One B-rep face of a CAD part: STEP entity #914.
In plain terms, the planar face has unit normal (1, 0, 0).
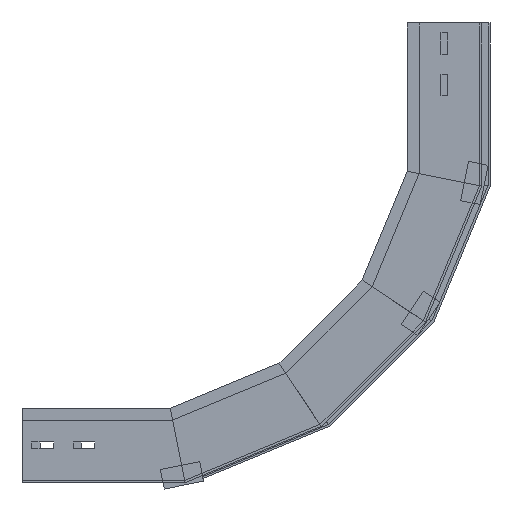
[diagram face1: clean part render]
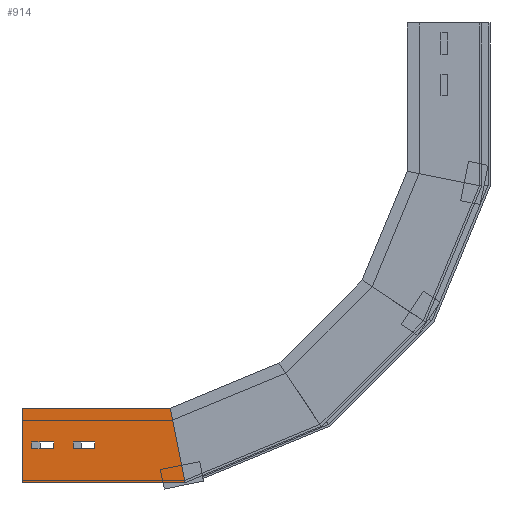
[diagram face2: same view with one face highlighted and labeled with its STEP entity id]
Its self-contained STEP definition (entity closure, numbers rounded to 3 decimals):
#3 = EDGE_CURVE ( 'NONE', #1530, #522, #280, .T. ) ;
#11 = CARTESIAN_POINT ( 'NONE',  ( 0., 41., -31.835 ) ) ;
#18 = ORIENTED_EDGE ( 'NONE', *, *, #1451, .T. ) ;
#43 = PLANE ( 'NONE',  #608 ) ;
#54 = CARTESIAN_POINT ( 'NONE',  ( 0., 0., -164.6 ) ) ;
#83 = CARTESIAN_POINT ( 'NONE',  ( 0., 41., -73.505 ) ) ;
#112 = CARTESIAN_POINT ( 'NONE',  ( 0., 34., -73.505 ) ) ;
#125 = DIRECTION ( 'NONE',  ( 0., -1., 0. ) ) ;
#147 = VERTEX_POINT ( 'NONE', #1470 ) ;
#148 = VECTOR ( 'NONE', #1207, 1000. ) ;
#162 = DIRECTION ( 'NONE',  ( -1., 0., 0. ) ) ;
#205 = FACE_BOUND ( 'NONE', #777, .T. ) ;
#280 = LINE ( 'NONE', #1710, #698 ) ;
#296 = CARTESIAN_POINT ( 'NONE',  ( 0., 75., 0. ) ) ;
#346 = ORIENTED_EDGE ( 'NONE', *, *, #1450, .F. ) ;
#369 = EDGE_CURVE ( 'NONE', #1091, #568, #1124, .T. ) ;
#379 = EDGE_CURVE ( 'NONE', #852, #602, #1860, .T. ) ;
#391 = VECTOR ( 'NONE', #1684, 1000. ) ;
#394 = CARTESIAN_POINT ( 'NONE',  ( 0., 0., 0. ) ) ;
#437 = EDGE_LOOP ( 'NONE', ( #1724, #1881, #18, #621 ) ) ;
#443 = LINE ( 'NONE', #1337, #1491 ) ;
#459 = CARTESIAN_POINT ( 'NONE',  ( 0., 0., 0. ) ) ;
#468 = DIRECTION ( 'NONE',  ( 0., 0., 1. ) ) ;
#469 = VERTEX_POINT ( 'NONE', #737 ) ;
#482 = LINE ( 'NONE', #781, #148 ) ;
#497 = CARTESIAN_POINT ( 'NONE',  ( 0., 75., -149.682 ) ) ;
#520 = CARTESIAN_POINT ( 'NONE',  ( 0., 41., -31.835 ) ) ;
#522 = VERTEX_POINT ( 'NONE', #1769 ) ;
#568 = VERTEX_POINT ( 'NONE', #54 ) ;
#575 = VECTOR ( 'NONE', #1275, 1000. ) ;
#597 = EDGE_CURVE ( 'NONE', #522, #469, #482, .T. ) ;
#602 = VERTEX_POINT ( 'NONE', #497 ) ;
#608 = AXIS2_PLACEMENT_3D ( 'NONE', #459, #162, #468 ) ;
#621 = ORIENTED_EDGE ( 'NONE', *, *, #3, .T. ) ;
#655 = LINE ( 'NONE', #1243, #1762 ) ;
#658 = CARTESIAN_POINT ( 'NONE',  ( 0., 34., -9.835 ) ) ;
#663 = VERTEX_POINT ( 'NONE', #83 ) ;
#666 = VECTOR ( 'NONE', #950, 1000. ) ;
#696 = LINE ( 'NONE', #1547, #1041 ) ;
#698 = VECTOR ( 'NONE', #850, 1000. ) ;
#720 = DIRECTION ( 'NONE',  ( 0., 1., 0. ) ) ;
#737 = CARTESIAN_POINT ( 'NONE',  ( 0., 41., -51.505 ) ) ;
#741 = EDGE_CURVE ( 'NONE', #469, #663, #655, .T. ) ;
#751 = ORIENTED_EDGE ( 'NONE', *, *, #1341, .T. ) ;
#777 = EDGE_LOOP ( 'NONE', ( #1654, #1785, #751, #1170 ) ) ;
#781 = CARTESIAN_POINT ( 'NONE',  ( 0., 41., -51.505 ) ) ;
#783 = CARTESIAN_POINT ( 'NONE',  ( 0., 41., -9.835 ) ) ;
#787 = VERTEX_POINT ( 'NONE', #11 ) ;
#795 = ORIENTED_EDGE ( 'NONE', *, *, #369, .T. ) ;
#814 = LINE ( 'NONE', #783, #666 ) ;
#849 = CARTESIAN_POINT ( 'NONE',  ( 0., 41., -9.835 ) ) ;
#850 = DIRECTION ( 'NONE',  ( 0., 0., 1. ) ) ;
#852 = VERTEX_POINT ( 'NONE', #296 ) ;
#856 = DIRECTION ( 'NONE',  ( 0., 0., 1. ) ) ;
#914 = ADVANCED_FACE ( 'NONE', ( #1775, #1767, #205 ), #43, .F. ) ;
#918 = VECTOR ( 'NONE', #1132, 1000. ) ;
#950 = DIRECTION ( 'NONE',  ( 0., 0., -1. ) ) ;
#964 = LINE ( 'NONE', #520, #1310 ) ;
#1005 = LINE ( 'NONE', #1259, #1793 ) ;
#1014 = VECTOR ( 'NONE', #1209, 1000. ) ;
#1041 = VECTOR ( 'NONE', #125, 1000. ) ;
#1045 = ORIENTED_EDGE ( 'NONE', *, *, #379, .F. ) ;
#1072 = LINE ( 'NONE', #1085, #1014 ) ;
#1085 = CARTESIAN_POINT ( 'NONE',  ( 0., 0., 0. ) ) ;
#1091 = VERTEX_POINT ( 'NONE', #394 ) ;
#1097 = EDGE_LOOP ( 'NONE', ( #1045, #1400, #795, #346 ) ) ;
#1124 = LINE ( 'NONE', #1140, #575 ) ;
#1132 = DIRECTION ( 'NONE',  ( 0., -0.981, -0.195 ) ) ;
#1140 = CARTESIAN_POINT ( 'NONE',  ( 0., 0., 0. ) ) ;
#1170 = ORIENTED_EDGE ( 'NONE', *, *, #1537, .T. ) ;
#1207 = DIRECTION ( 'NONE',  ( 0., 1., 0. ) ) ;
#1209 = DIRECTION ( 'NONE',  ( 0., 1., 0. ) ) ;
#1243 = CARTESIAN_POINT ( 'NONE',  ( 0., 41., -51.505 ) ) ;
#1258 = CARTESIAN_POINT ( 'NONE',  ( 0., 75., 0. ) ) ;
#1259 = CARTESIAN_POINT ( 'NONE',  ( 0., 34., -9.835 ) ) ;
#1275 = DIRECTION ( 'NONE',  ( 0., 0., -1. ) ) ;
#1310 = VECTOR ( 'NONE', #1806, 1000. ) ;
#1318 = EDGE_CURVE ( 'NONE', #1091, #852, #1072, .T. ) ;
#1331 = EDGE_CURVE ( 'NONE', #1501, #787, #814, .T. ) ;
#1337 = CARTESIAN_POINT ( 'NONE',  ( 0., 41., -9.835 ) ) ;
#1341 = EDGE_CURVE ( 'NONE', #787, #147, #964, .T. ) ;
#1400 = ORIENTED_EDGE ( 'NONE', *, *, #1318, .F. ) ;
#1432 = VERTEX_POINT ( 'NONE', #658 ) ;
#1450 = EDGE_CURVE ( 'NONE', #602, #568, #1709, .T. ) ;
#1451 = EDGE_CURVE ( 'NONE', #663, #1530, #696, .T. ) ;
#1470 = CARTESIAN_POINT ( 'NONE',  ( 0., 34., -31.835 ) ) ;
#1491 = VECTOR ( 'NONE', #720, 1000. ) ;
#1501 = VERTEX_POINT ( 'NONE', #849 ) ;
#1530 = VERTEX_POINT ( 'NONE', #112 ) ;
#1537 = EDGE_CURVE ( 'NONE', #147, #1432, #1005, .T. ) ;
#1547 = CARTESIAN_POINT ( 'NONE',  ( 0., 41., -73.505 ) ) ;
#1627 = EDGE_CURVE ( 'NONE', #1432, #1501, #443, .T. ) ;
#1654 = ORIENTED_EDGE ( 'NONE', *, *, #1627, .T. ) ;
#1684 = DIRECTION ( 'NONE',  ( 0., 0., -1. ) ) ;
#1698 = CARTESIAN_POINT ( 'NONE',  ( 0., 31.495, -158.335 ) ) ;
#1709 = LINE ( 'NONE', #1698, #918 ) ;
#1710 = CARTESIAN_POINT ( 'NONE',  ( 0., 34., -51.505 ) ) ;
#1724 = ORIENTED_EDGE ( 'NONE', *, *, #597, .T. ) ;
#1762 = VECTOR ( 'NONE', #1821, 1000. ) ;
#1767 = FACE_OUTER_BOUND ( 'NONE', #1097, .T. ) ;
#1769 = CARTESIAN_POINT ( 'NONE',  ( 0., 34., -51.505 ) ) ;
#1775 = FACE_BOUND ( 'NONE', #437, .T. ) ;
#1785 = ORIENTED_EDGE ( 'NONE', *, *, #1331, .T. ) ;
#1793 = VECTOR ( 'NONE', #856, 1000. ) ;
#1806 = DIRECTION ( 'NONE',  ( 0., -1., 0. ) ) ;
#1821 = DIRECTION ( 'NONE',  ( 0., 0., -1. ) ) ;
#1860 = LINE ( 'NONE', #1258, #391 ) ;
#1881 = ORIENTED_EDGE ( 'NONE', *, *, #741, .T. ) ;
